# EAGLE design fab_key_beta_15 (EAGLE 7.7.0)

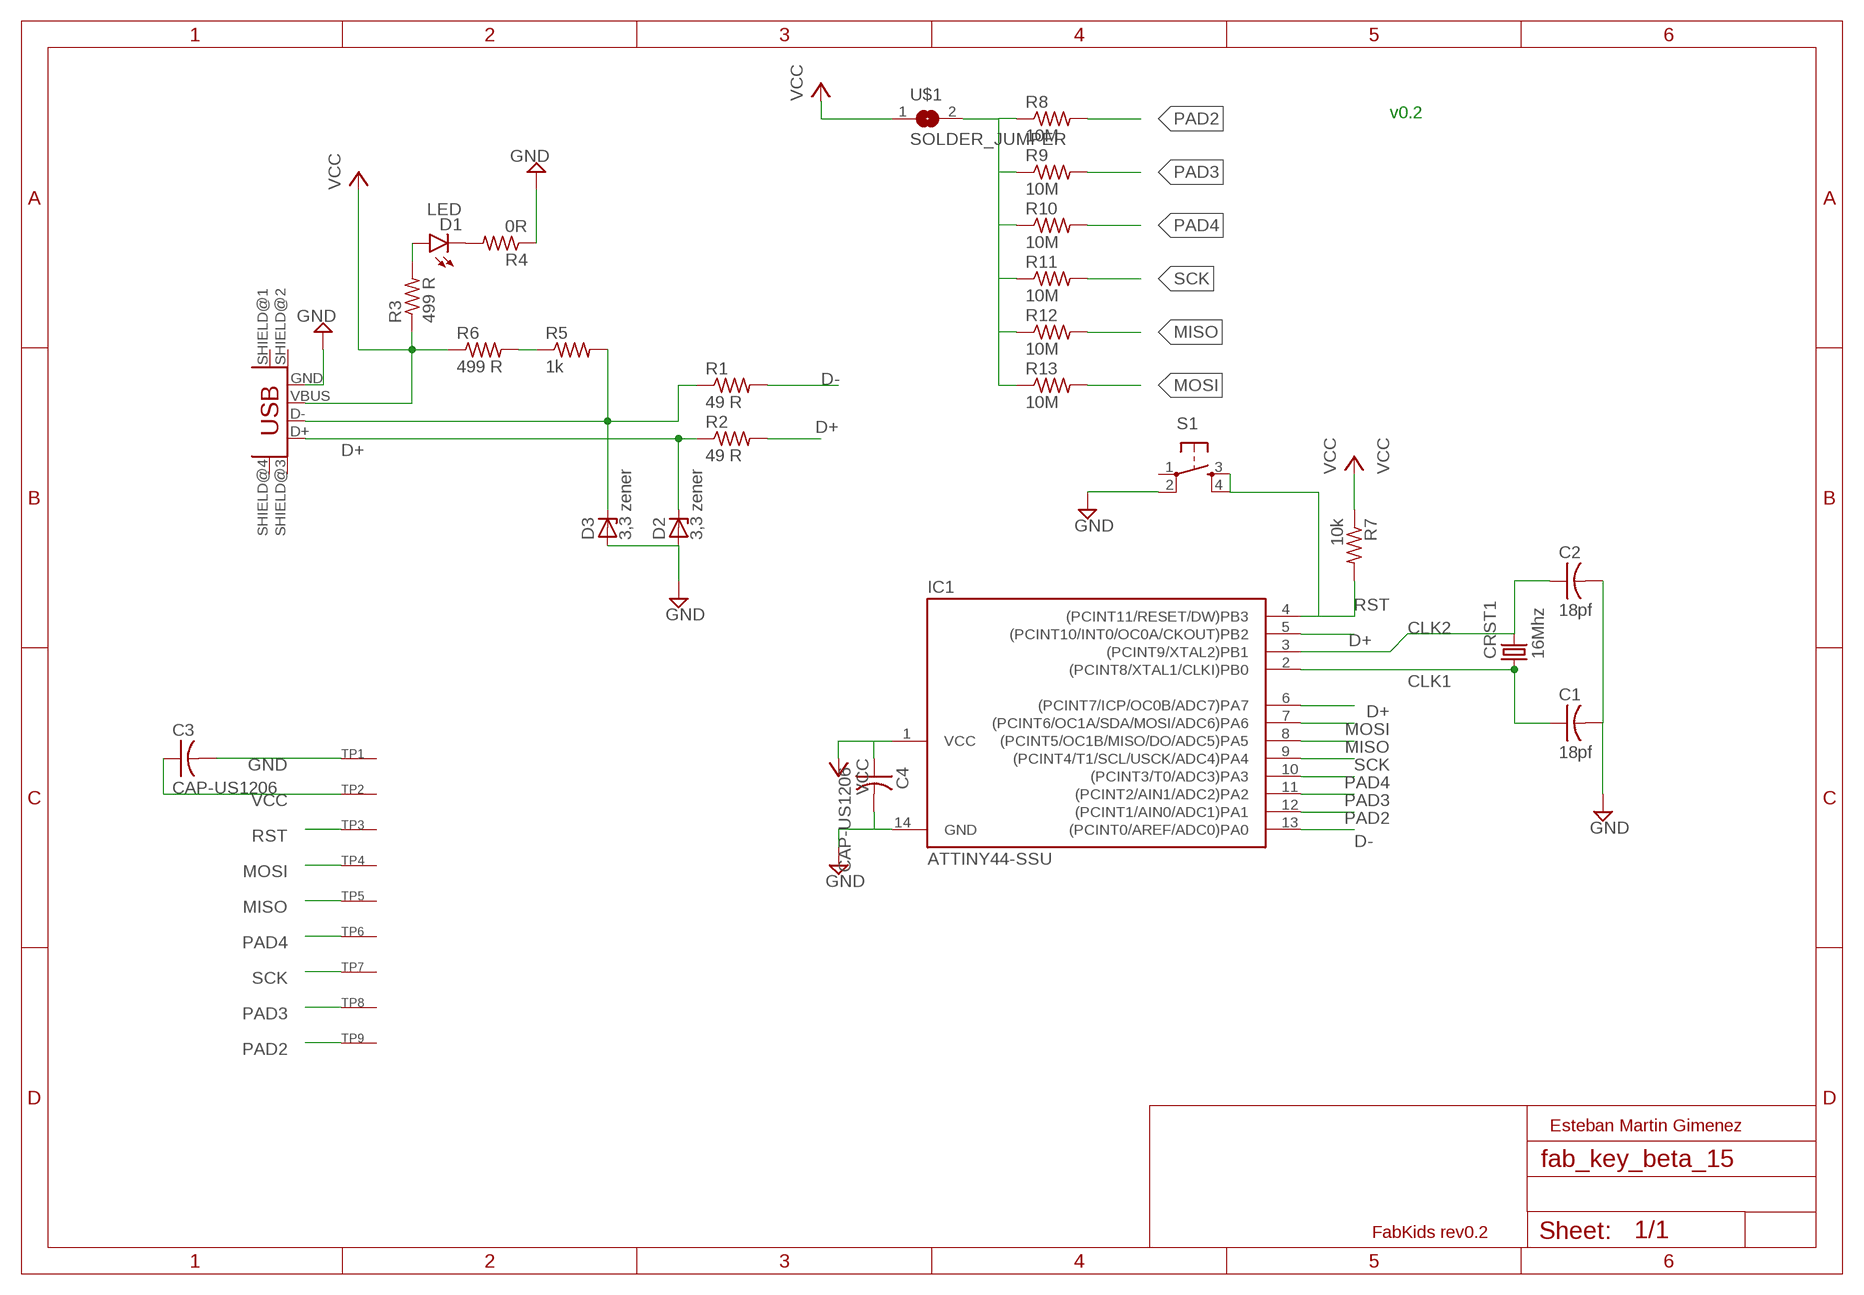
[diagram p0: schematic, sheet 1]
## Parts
C1  18pf  CAP-US1206FAB  [C1206FAB]
C2  18pf  CAP-US1206FAB  [C1206FAB]
C3  CAP-US1206  [C1206]
C4  CAP-US1206  [C1206]
CRST1  16Mhz  CRYSTAL  [2-SMD-5X3MM]
D1  LED  LED1206  [LED-1206]
D2  3,3 zener  ZENER_DIODESOD123  [SOD123]
D3  3,3 zener  ZENER_DIODESOD123  [SOD123]
IC1  ATTINY44-SSU  [SOIC14]
MINIUSB  USB_MINIB  [USB_MINIB]
R1  49 R  RES-US1206FAB  [R1206FAB]
R2  49 R  RES-US1206FAB  [R1206FAB]
R3  499 R  RES-US1206FAB  [R1206FAB]
R4  0R  RES-US1206FAB  [R1206FAB]
R5  1k  RES-US1206FAB  [R1206FAB]
R6  499 R  RES-US1206FAB  [R1206FAB]
R7  10k  RES-US1206FAB  [R1206FAB]
R8  10M  RES-US1206FAB  [R1206FAB]
R9  10M  RES-US1206FAB  [R1206FAB]
R10  10M  RES-US1206FAB  [R1206FAB]
R11  10M  RES-US1206FAB  [R1206FAB]
R12  10M  RES-US1206FAB  [R1206FAB]
R13  10M  RES-US1206FAB  [R1206FAB]
S1  6MM_SWITCH6MM_SWITCH  [6MM_SWITCH]
TP1  SEWTAPBIG  [BIGTAP]
TP2  SEWTAPBIG  [BIGTAP]
TP3  SEWTAPBIG  [BIGTAP]
TP4  SEWTAPBIG  [BIGTAP]
TP5  SEWTAPBIG  [BIGTAP]
TP6  SEWTAPBIG  [BIGTAP]
TP7  SEWTAPBIG  [BIGTAP]
TP8  SEWTAPBIG  [BIGTAP]
TP9  SEWTAPBIG  [BIGTAP]
U$1  SOLDER_JUMPER  [SJFAB]

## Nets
CLK1: C1.1 CRST1.P$1 IC1.2((PCINT8/XTAL1/CLKI)PB0)
CLK2: C2.1 CRST1.P$2 IC1.3((PCINT9/XTAL2)PB1)
D+: D2.CATHODE IC1.5((PCINT10/INT0/OC0A/CKOUT)PB2) IC1.6((PCINT7/ICP/OC0B/ADC7)PA7) MINIUSB.D+ R2.1 R2.2
D-: D3.CATHODE IC1.13((PCINT0/AREF/ADC0)PA0) MINIUSB.D- R1.1 R1.2 R5.2
GND: C1.2 C2.2 C3.2 C4.2 D2.ANODE D3.ANODE IC1.14(GND) MINIUSB.GND R4.1 S1.2(P1) TP1.P$1(SEW)
MISO: IC1.8((PCINT5/OC1B/MISO/DO/ADC5)PA5) R12.2 TP5.P$1(SEW)
MOSI: IC1.7((PCINT6/OC1A/SDA/MOSI/ADC6)PA6) R13.2 TP4.P$1(SEW)
N$1: R8.1 R9.1 R10.1 R11.1 R12.1 R13.1 U$1.2
N$2: D1.C R4.2
N$8: D1.A R3.2
N$9: R5.1 R6.2
PAD2: IC1.12((PCINT1/AIN0/ADC1)PA1) R8.2 TP9.P$1(SEW)
PAD3: IC1.11((PCINT2/AIN1/ADC2)PA2) R9.2 TP8.P$1(SEW)
PAD4: IC1.10((PCINT3/T0/ADC3)PA3) R10.2 TP6.P$1(SEW)
RST: IC1.4((PCINT11/RESET/DW)PB3) R7.2 S1.3(S) S1.4(S1) TP3.P$1(SEW)
SCK: IC1.9((PCINT4/T1/SCL/USCK/ADC4)PA4) R11.2 TP7.P$1(SEW)
VCC: C3.1 C4.1 IC1.1(VCC) MINIUSB.VBUS R3.1 R6.1 R7.1 TP2.P$1(SEW) U$1.1
Unconnected: MINIUSB.SHIELD@1(SHIELD) MINIUSB.SHIELD@2(SHIELD1) MINIUSB.SHIELD@3(SHIELD2) MINIUSB.SHIELD@4(SHIELD3) S1.1(P)

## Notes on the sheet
- v0.2
- Esteban Martin Gimenez
- FabKids rev0.2

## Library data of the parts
C1-C4 = fab:CAP-US
CRST1 = fab:CRYSTAL
D1 = SparkFun-LED:LED: LEDs
D2 D3 = fab:ZENER_DIODE: zener diode
IC1 = fab:ATTINY44
MINIUSB = fab:USB_MINIB
R1-R13 = fab:RES-US: Resistor (US Symbol)
S1 = fab:6MM_SWITCH: OMRON SWITCH
TP1-TP9 = adafruit:SEWTAP
U$1 = fab:SOLDER_JUMPER

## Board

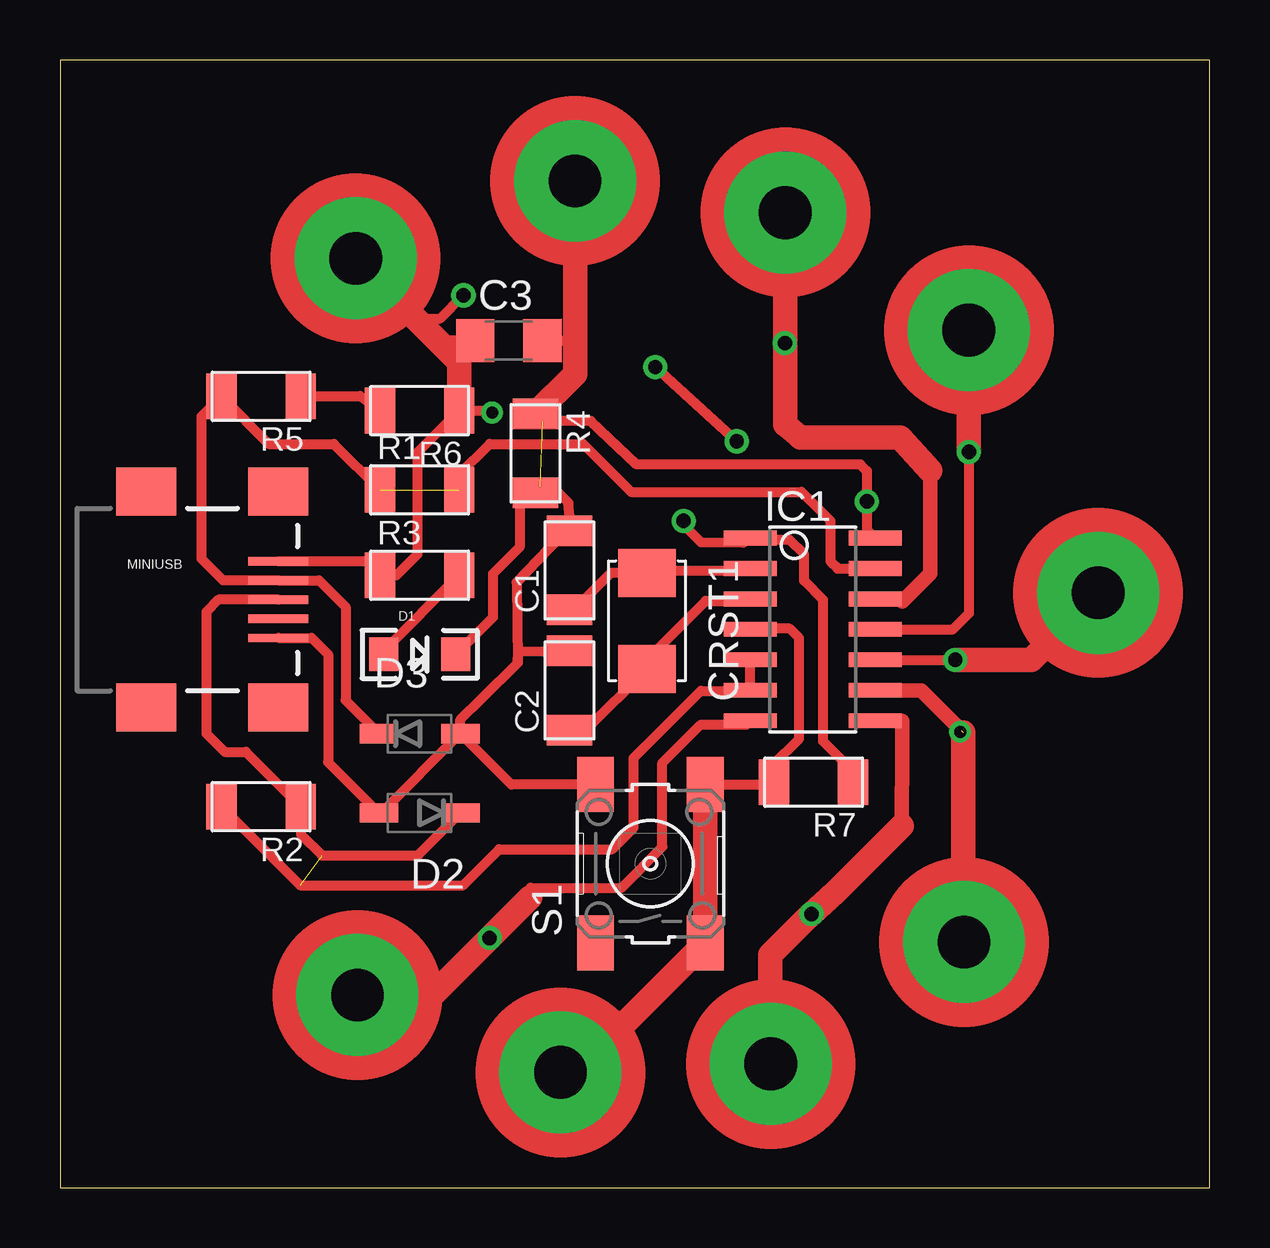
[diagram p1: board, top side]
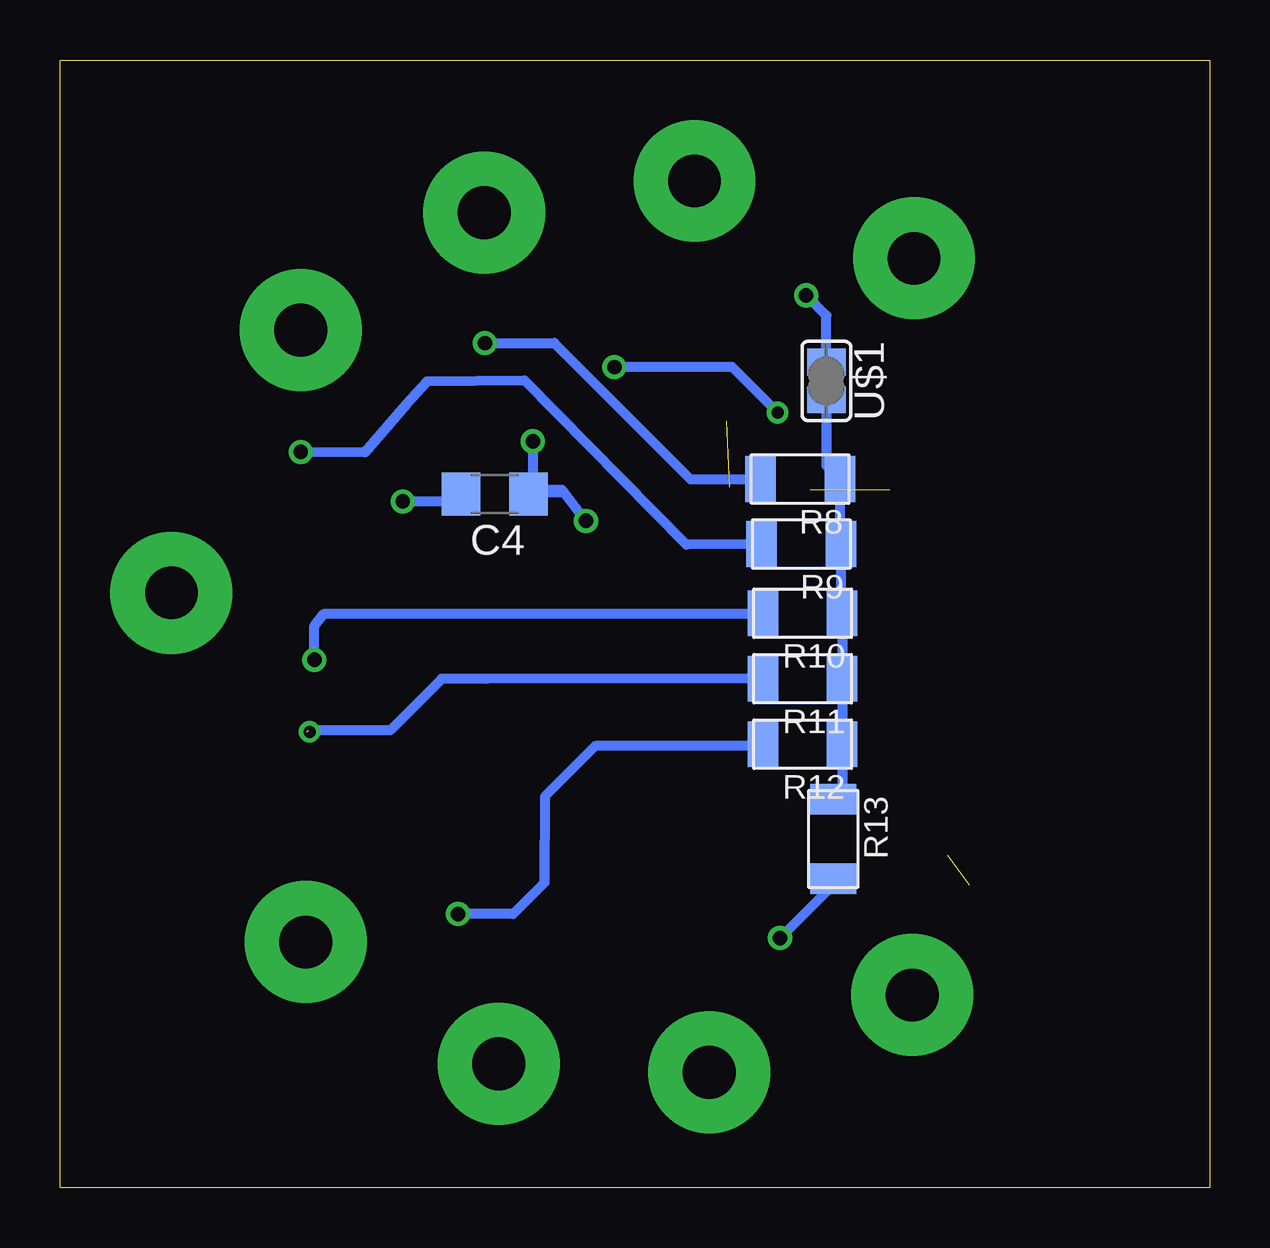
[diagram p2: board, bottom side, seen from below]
Size 47.9 x 47 mm. Coordinates in mm from the lower left corner, seen from the top.
Outline: 0,0 47.9,0 47.9,47 0,47 0,0
Copper layers (1*16): Top 0.035mm / dielectric 1.5mm / Bottom 0.035mm
Design rules "board12_1_3_5v": minimum track width 10mil, minimum drill 24mil, track to track 16mil, track to pad 0.205mm, pad to pad 0.205mm, via to via 0.205mm, smd to smd 6mil, copper to edge 40mil, drill to drill 8mil, minimum pad ring 10mil, minimum via ring 8mil, stop-mask expansion 4mil, vias tented up to drill 0mil, thermal gap 10mil

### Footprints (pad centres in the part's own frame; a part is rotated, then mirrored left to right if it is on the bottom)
C1206FAB = smd 1.27 x 1.905: 1 -1.651,0; 2 1.651,0
C1206 = smd 1.6 x 1.8: 1 -1.4,0; 2 1.4,0
2-SMD-5X3MM = smd 2 x 2.4: P$1 -2,0; P$2 2,0
LED-1206 = smd 1.2 x 1.4: A -1.5,0; C 1.5,0
SOD123 = smd 1.6 x 0.8: ANODE 1.7,0; CATHODE -1.7,0
SOIC14 = smd 0.61 x 2.21: 1 -3.81,-2.603; 2 -2.54,-2.603; 3 -1.27,-2.603; 4 0,-2.603; 5 1.27,-2.603; 6 2.54,-2.603; 7 3.81,-2.603; 8 3.81,2.603; 9 2.54,2.603; 10 1.27,2.603; 11 0,2.603; 12 -1.27,2.603; 13 -2.54,2.603; 14 -3.81,2.603
USB_MINIB = smd 2.5 x 0.35: D+ 3.77,0; D- 3.77,0.8; GND 3.77,-1.6; ID 3.77,-0.8; VBUS 3.77,1.6 | smd 2.5 x 2: SHIELD@1 -1.73,-4.5; SHIELD@2 -1.73,4.5; SHIELD@3 3.77,4.5; SHIELD@4 3.77,-4.5
R1206FAB = smd 1.27 x 1.905: 1 -1.651,0; 2 1.651,0
6MM_SWITCH = smd 2.286 x 1.524: 1 -3.302,2.286; 2 3.302,2.286; 3 -3.302,-2.286; 4 3.302,-2.286
BIGTAP = drill 2.2 pad 5.08: P$1 0,0
SJFAB = smd 1.118 x 1.6: 1 -0.787,0; 2 0.787,0

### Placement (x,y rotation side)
C1  21.23,25.73 90 top
C2  21.23,20.72 90 top
C3  18.7,35.3 0 top
C4  29.78,28.9 180 bottom
CRST1  24.46,23.62 270 top
D1  14.98,22.22 0 top
D2  14.98,15.62 180 top
D3  14.98,18.92 0 top
IC1  31.37,23.26 270 top
MINIUSB  5.33,24.51 0 top
R1  14.98,29.08 0 top
R2  8.38,15.87 180 top
R3  14.98,25.52 0 top
R4  19.81,30.6 270 top
R5  8.38,32.98 180 top
R6  14.98,32.38 180 top
R7  31.4,16.9 180 top
R8  17.06,29.53 180 bottom
R9  17.01,26.82 180 bottom
R10  16.96,23.94 180 bottom
R11  16.96,21.21 180 bottom
R12  16.96,18.48 180 bottom
R13  15.68,14.53 270 bottom
S1  24.6,13.5 90 top
TP1  21.46,41.96 0 top
TP2  12.32,38.73 0 top
TP3  20.85,4.8 0 top
TP4  12.39,8.02 0 top
TP5  29.61,5.15 0 top
TP6  43.26,24.79 0 top
TP7  37.67,10.23 0 top
TP8  37.87,35.73 0 top
TP9  30.22,40.64 0 top
U$1  15.97,33.62 270 bottom

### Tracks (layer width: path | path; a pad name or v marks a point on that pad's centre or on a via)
CLK1
  Top 0.406: C1.1 21.41,24.08 22.96,25.62 CRST1.P$1 25.47,25.62 25.58,25.73 28.69,25.73 IC1.2
CLK2
  Top 0.406: C2.1 21.91,19.07 CRST1.P$2 24.46,22.02 26.9,24.46 28.69,24.46 IC1.3
D+  (1 unrouted)
  Top 0.406: IC1.5 IC1.6 28.74,20.7 26.7,20.7 23.9,17.9 23.9,15 23,14.1 18.3,14.1 16.8,12.6 10,12.6 R2.2 | MINIUSB.D+ 6.6,24.51 6.09,24 6.09,18.92 6.86,18.16 7.75,18.16 R2.1 10.03,14.73 10.92,13.84 14.91,13.84 D2.CATHODE
D-  (1 unrouted)
  Top 0.406: R1.2 16.64,29.73 17.9,31 21.8,31 23.8,29 30.9,29 32.1,27.8 32.1,26.1 32.4,25.8 IC1.13 | R1.1 11.41,31 8.7,31 R5.2 5.9,32.15 5.9,26.2 6.79,25.31 MINIUSB.D- 10.79,25.31 11.9,24.2 11.9,20.3 D3.CATHODE
GND  (via drill 0.6 pad 0.61)  (1 unrouted)
  Top 0.406: D3.ANODE 13.38,15.62 D2.ANODE 11.17,17.73 11.17,22.22 10.49,22.91 MINIUSB.GND | D3.ANODE 16.68,19.5 17.57,20.39 19.07,21.87 | 19.07,21.87 19.1,22.35 C2.2 | C1.2 21.28,27.58 | 21.28,27.58 19.02,25.22 19.07,21.87 | 21.28,27.58 21.18,28.55 20.55,29.18 20.02,29.18 20,29.2 | 33.22,27.07 IC1.14 33.62,27.42 v33.62,28.6 33.62,29.87 33.35,30.14 24.02,30.14 22.12,31.95 20.12,31.95 R4.1 | S1.2 18.8,16.8 D3.ANODE | C3.2 21.46,35.3
  Top 1.016: TP1.P$1 21.46,35.3 21.46,33.91 R4.1
  Bottom 0.406: C4.2 31.19,28.7 31.08,28.6 v33.62,28.6
MISO  (via drill 0.6)
  Top 0.406: 29.6,5.17 TP5.P$1
  Top 0.61: IC1.8 35.1,19.45 35.1,18.4 35.07,15.07
  Top 1.016: 35.07,15.07 32.3,12.3 v31.31,11.4 31.2,11.3 29.6,9.7 29.6,5.17
  Bottom 0.406: v31.31,11.4 29.02,11.4 27.72,12.71 27.7,16.3 25.6,18.4 18.5,18.4 R12.2
MOSI  (via drill 0.6)
  Top 0.406: 19.6,12.1 19.6,12.5 23.4,12.5 25.1,14.2 25.1,17.7 26.7,19.3 28.61,19.3 IC1.7
  Top 1.016: TP4.P$1 15.52,8.02 v17.9,10.4 19.6,12.1
  Bottom 0.406: R13.2 15.68,12.62 v17.9,10.4
N$1
  Bottom 0.406: U$1.2 15.97,30.09 R8.1 15.41,26.87 R9.1 15.36,23.99 R10.1 R11.1 R12.1 15.31,16.55 R13.1
N$2
  Top 0.406: R4.2 19.15,28.93 19.15,26.69 18.03,25.57 18.03,23.77 D1.C
N$4  (via drill 0.5)
  other vias: 37.5,19
N$8
  Top 0.406: D1.A 13.46,22.22 13.46,22.35 R3.2
N$9
  Top 0.406: R5.1 10.1,32.98 12.5,33 R6.2
PAD2  (via drill 0.6)
  Top 0.406: 35.1,24.43 34.07,24.43 IC1.12 | 30.22,31.8 30.22,34.28 v30.2,35.2
  Top 0.61: 36.27,29.89 36.27,25.6 35.1,24.43
  Top 1.016: TP9.P$1 30.22,31.8 30.86,31.26 35,31.26 36.27,29.89
  Bottom 0.406: v30.2,35.2 27.3,35.2 21.63,29.53 R8.2
PAD3  (via drill 0.6)
  Top 0.406: v37.87,30.66 37.87,23.93 37.2,23.26 IC1.11
  Top 1.016: TP8.P$1 v37.87,30.66
  Bottom 0.406: 37.94,30.69 v37.87,30.66 35.2,30.64 33.46,32.64 32.6,33.6 28.54,33.64 21.8,26.8 R9.2
PAD4  (via drill 0.6)
  Top 0.406: IC1.10 v37.3,21.99
  Top 1.016: v37.3,21.99 40.46,21.99 TP6.P$1
  Bottom 0.406: v37.3,21.99 37.3,23.42 36.92,23.9 18.9,23.9 18.7,23.7 R10.2
RST
  Top 0.406: S1.4 29.65,16.8 R7.2 29.75,17.65 30.8,18.7 30.8,22.9 30.4,23.3 28.8,23.3 IC1.4
  Top 1.016: TP3.P$1 21.48,4.8 S1.3 S1.4
SCK  (1 unrouted)
  Top 0.406: 37.64,10.26 TP7.P$1
  Top 0.61: IC1.9 35.89,20.72 37.64,18.97
  Top 1.016: 37.64,18.97 37.64,10.26
  Bottom 0.406: 37.56,19.06 34.14,19.06 32,21.2 30.11,21.2 R11.2
VCC  (via drill 0.5, 0.6, 0.6 pad 0.61)
  Top 0.406: R7.1 33.05,17.35 31.8,18.6 31.8,24.5 31,25.3 31,26.4 30.4,27 28.84,27 IC1.1 28.45,26.88 26.7,26.9 25.98,27.62 v25.98,27.78 | C3.1 15.48,35.3 14.38,36.67 | MINIUSB.VBUS 12.75,26.11 R3.1 14.02,25.52 14.9,26.4 14.9,30.65 R6.1 18,32.38 v18,32.3 | TP2.P$1 12.32,38.47 14.57,36.22 15.84,36.22 v16.81,37.19 | v24.8,34.2 v28.2,31.1
  Top 1.016: TP2.P$1 14.38,36.67 16.64,34.41 R6.1
  Bottom 0.406: C4.1 28.38,28.98 27,29 28.2,29.1 | 28.2,29.1 26.98,29.08 v25.98,27.78 | U$1.1 15.97,36.35 v16.81,37.19 | v18,32.3 19.9,34.2 v24.8,34.2 | v28.2,31.1 28.2,29.1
